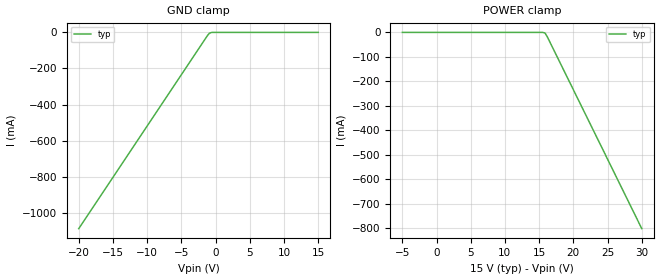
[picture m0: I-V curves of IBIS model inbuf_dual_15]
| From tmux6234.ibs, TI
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| inbuf_dual_15
[Model]   inbuf_dual_15
Model_type   Input
|   typ   min   max
C_comp   6.362683e-13   NA   NA
[Voltage Range]   15   NA   NA
[Temperature Range]   27   NA   NA
[Power Clamp Reference]   15   NA   NA
[GND Clamp Reference]   0   NA   NA
[GND Clamp]
|   Voltage   I(typ)   I(min)   I(max)
-20V      -1.088A    NA         NA
-1.263V   -21.76mA   NA         NA
-909.1mV  -4.356mA   NA         NA
-555.6mV  -13.15uA   NA         NA
15V       556.6nA    NA         NA
[POWER Clamp]
|   Voltage   I(typ)   I(min)   I(max)
-5V       556.8nA    NA         NA
15.51V    -7.687uA   NA         NA
15.86V    -2.503mA   NA         NA
16.21V    -19.1mA    NA         NA
30V       -802.5mA   NA         NA
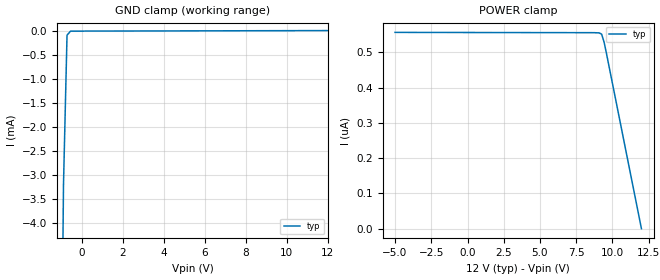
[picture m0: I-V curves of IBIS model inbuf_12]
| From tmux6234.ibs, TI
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| inbuf_12
[Model]   inbuf_12
Model_type   Input
|   typ   min   max
C_comp   4.014581e-13   NA   NA
[Voltage Range]   12   NA   NA
[Temperature Range]   27   NA   NA
[Power Clamp Reference]   12   NA   NA
[GND Clamp Reference]   0   NA   NA
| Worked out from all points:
|   GND clamp passes 1 mA (typ) near -0.76 V on its own axis
[GND Clamp]
|   Voltage   I(typ)   I(min)   I(max)
-5V       -231.7mA   NA         NA
-1.051V   -10.83mA   NA         NA
-878.8mV  -3.196mA   NA         NA
-707.1mV  -96.02uA   NA         NA
-535.4mV  -10.8uA    NA         NA
12V       556.4nA    NA         NA
[POWER Clamp]
|   Voltage   I(typ)   I(min)   I(max)
-5V       556.7nA    NA         NA
8.737V    555.9nA    NA         NA
9.081V    555.3nA    NA         NA
9.253V    551.7nA    NA         NA
9.424V    529.1nA    NA         NA
9.596V    495.3nA    NA         NA
12V       -67.66pA   NA         NA
